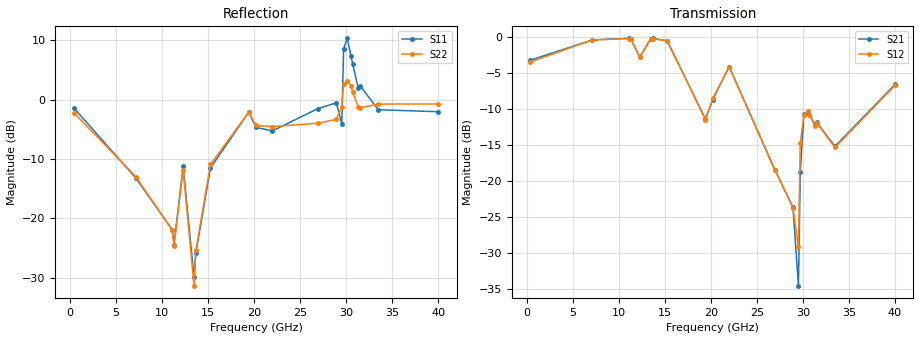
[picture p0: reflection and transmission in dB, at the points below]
! Network Analyzer HP8722ES.07.66: Jul 25, 2000 Serial No. US39175408
! 26 Oct 2004  13:47:28
! Frequency  S11  S21  S12  S22
# HZ  S  DB R  50
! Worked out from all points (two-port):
!   201 points, 400 MHz to 40 GHz, reference 50 ohm
!   highest |S21| = -0.21 dB at 11.09 GHz (marker M1); lowest = -34.6 dB at 29.51 GHz (marker M2)
!   |S21| within 3 dB of the highest: 405.4 MHz to 17.52 GHz (17.12 GHz wide, 191 % of centre)
!   lowest |S11| = -29.9 dB at 13.47 GHz (marker M3), VSWR 1.07, Z = 52.9 - j1.51 ohm
!   |S11| at or under -10 dB: 1.486 GHz to 15.58 GHz (14.09 GHz wide, 165 % of centre)
!   |S22| runs from -39.7 to 3.6 dB; largest |S21 - S12| = 0.071
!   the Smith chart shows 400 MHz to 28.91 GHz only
!   S11 on the Smith chart (normalised r, x): 400 MHz: 0.55, -2.38; 11.29 GHz: 0.97, -0.11; 15.25 GHz: 1.69, +0.20; 19.41 GHz: 0.56, -1.83; 21.98 GHz: 1.98, -1.55; 28.91 GHz: 0.26, -2.66
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4e8  -1.38 -43.9  -3.24 48.1  -3.49 53.2  -2.19 -35.1
7.132e9  -13.18 -106.0  -0.43 -22.5  -0.43 -22.7  -12.97 -119.9
1.1092e10  -21.92 -110.7  -0.21 -43.1  -0.25 -43.0  -21.93 -144.4
1.129e10  -24.45 -103.9  -0.28 -44.9  -0.25 -44.7  -24.74 -145.0
1.228e10  -11.25 -53.3  -2.81 -49.3  -2.82 -48.6  -11.87 -52.0
1.3468e10  -29.92 -26.6  -0.25 -53.2  -0.27 -53.2  -31.35 25.9
1.3666e10  -25.82 2.0  -0.22 -55.5  -0.25 -55.3  -25.40 30.7
1.525e10  -11.52 12.1  -0.55 -71.2  -0.56 -71.4  -10.92 20.9
1.9408e10  -2.12 -54.0  -11.42 -105.7  -11.49 -105.5  -2.11 -40.7
2.02e10  -4.68 -75.7  -8.72 -53.2  -8.56 -53.3  -4.35 -65.7
2.1982e10  -5.26 -30.3  -4.14 -112.0  -4.16 -112.1  -4.54 -24.7
2.6932e10  -1.50 -56.2  -18.45 -25.7  -18.46 -24.5  -3.97 -58.9
2.8912e10  -0.55 -40.8  -23.69 -71.6  -23.75 -71.9  -3.33 -19.7
2.9506e10  -4.08 28.8  -34.57 -82.6  -29.25 -65.3  -1.19 34.3
2.9704e10  8.55 -64.0  -18.78 10.2  -14.80 19.9  2.58 -73.8
3.01e10  10.32 -63.2  -10.76 16.6  -10.83 16.2  3.16 -50.4
3.0496e10  7.42 -72.4  -10.42 -3.2  -10.26 -3.0  2.36 -72.1
3.0694e10  5.98 96.5  -10.82 -12.5  -10.80 -11.8  1.25 107.3
3.1288e10  1.95 88.8  -12.14 -24.4  -12.36 -24.8  -1.21 109.2
3.1486e10  2.36 -87.4  -11.86 -26.8  -11.94 -27.4  -1.36 -70.6
3.3466e10  -1.70 -53.3  -15.21 -9.8  -15.37 -9.6  -0.75 -53.1
4e10  -2.04 -76.8  -6.60 5.2  -6.74 5.6  -0.74 -38.7
